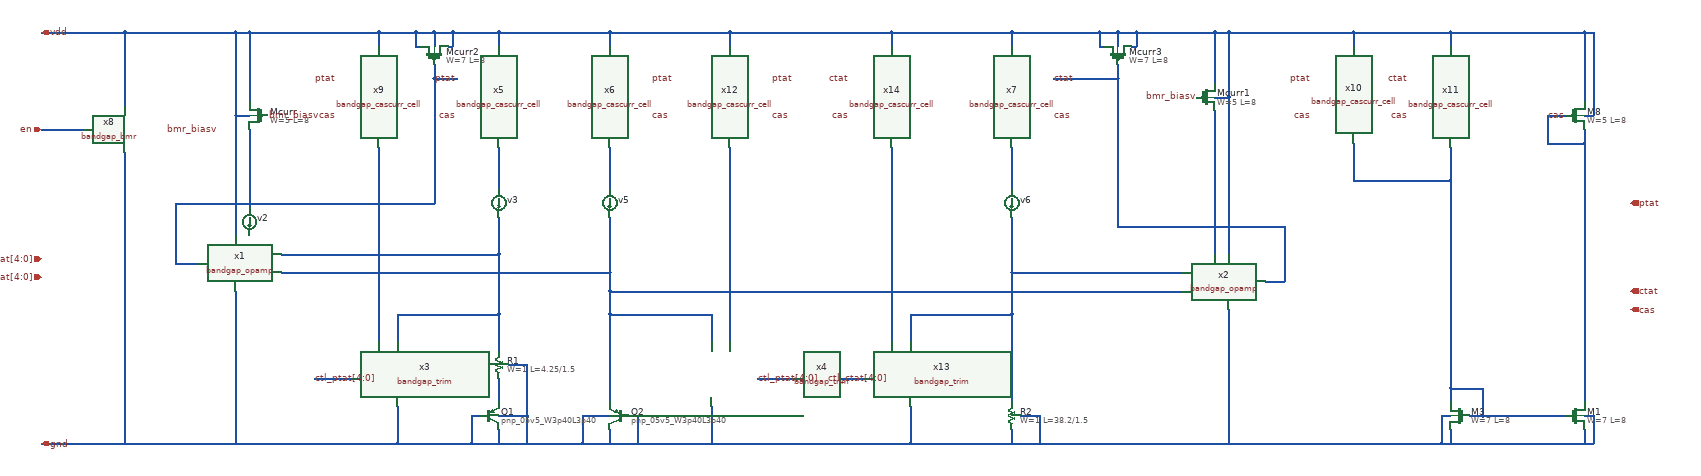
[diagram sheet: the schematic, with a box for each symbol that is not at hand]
v {xschem version=2.9.8 file_version=1.2}
G {}
K {}
V {}
S {}
E {}
N 1230 -280 1230 -90 {lab=#net1}
N 990 -410 990 -280 {lab=#net2}
N 990 -140 990 -90 {lab=#net3}
N 930 -60 950 -60 {lab=gnd}
N 930 -60 930 0 {lab=gnd}
N 930 0 990 0 {lab=gnd}
N 990 -30 990 0 {lab=gnd}
N 1230 -30 1230 0 {lab=gnd}
N 1230 0 1290 0 {lab=gnd}
N 1290 -60 1290 0 {lab=gnd}
N 1270 -60 1290 -60 {lab=gnd}
N 890 -890 990 -890 {lab=vdd}
N 990 -890 990 -860 {lab=vdd}
N 990 -890 1230 -890 {lab=vdd}
N 1230 -890 1230 -860 {lab=vdd}
N 1170 0 1230 0 {lab=gnd}
N 770 0 930 0 {lab=gnd}
N 2160 0 2570 0 {lab=gnd}
N 2100 -30 2100 0 {lab=gnd}
N 1230 -370 1230 -330 {lab=#net1}
N 1880 0 2100 0 {lab=gnd}
N 520 -410 990 -410 {lab=#net2}
N 520 -370 1230 -370 {lab=#net1}
N 290 -390 340 -390 {lab=ptat}
N 420 -330 420 0 {lab=gnd}
N 2570 -290 2570 0 {lab=gnd}
N 2100 -280 2100 -90 {lab=#net4}
N 2100 -370 2470 -370 {lab=#net4}
N 1840 -890 2100 -890 {lab=vdd}
N 420 -710 420 -450 {lab=vdd}
N 2570 -750 2570 -410 {lab=vdd}
N 2540 -890 2570 -890 {lab=vdd}
N 2100 -890 2100 -860 {lab=vdd}
N 3050 -890 3050 -860 {lab=vdd}
N 2840 -890 3050 -890 {lab=vdd}
N 2840 -890 2840 -860 {lab=vdd}
N 3050 -120 3050 -90 {lab=#net5}
N 2840 -650 2840 -570 {lab=#net5}
N 2840 -570 3050 -570 {lab=#net5}
N 3120 -60 3300 -60 {lab=#net5}
N 3050 -120 3120 -120 {lab=#net5}
N 3120 -120 3120 -60 {lab=#net5}
N 3050 0 3340 0 {lab=gnd}
N 3340 -30 3340 0 {lab=gnd}
N 3050 -30 3050 0 {lab=gnd}
N 3030 -60 3050 -60 {lab=gnd}
N 3030 -60 3030 0 {lab=gnd}
N 3340 -60 3360 -60 {lab=gnd}
N 3360 -60 3360 0 {lab=gnd}
N 3340 0 3360 0 {lab=gnd}
N 3340 -890 3340 -740 {lab=vdd}
N 3260 -710 3300 -710 {lab=cas}
N 3260 -710 3260 -650 {lab=cas}
N 3260 -650 3340 -650 {lab=cas}
N 3340 -680 3340 -650 {lab=cas}
N 3050 -890 3340 -890 {lab=vdd}
N 3340 -650 3340 -90 {lab=cas}
N 3340 -710 3360 -710 {lab=vdd}
N 3360 -890 3360 -710 {lab=vdd}
N 3340 -890 3360 -890 {lab=vdd}
N 2570 -890 2840 -890 {lab=vdd}
N 3050 -640 3050 -570 {lab=#net5}
N 3050 -570 3050 -120 {lab=#net5}
N 3090 -60 3120 -60 {lab=#net5}
N 3030 0 3050 0 {lab=gnd}
N 2570 0 3030 0 {lab=gnd}
N 2190 -790 2330 -790 {lab=ctat}
N 2690 -470 2690 -350 {lab=ctat}
N 2650 -350 2690 -350 {lab=ctat}
N 290 -520 290 -390 {lab=ptat}
N 290 -520 850 -520 {lab=ptat}
N 850 -790 850 -520 {lab=ptat}
N 850 -790 900 -790 {lab=ptat}
N 1230 -330 2470 -330 {lab=#net1}
N 180 -890 420 -890 {lab=vdd}
N 180 0 420 0 {lab=gnd}
N 990 -60 1050 -60 { lab=gnd}
N 1050 -60 1050 0 { lab=gnd}
N 1170 -60 1230 -60 { lab=gnd}
N 1170 -60 1170 0 { lab=gnd}
N 1010 -170 1050 -170 { lab=gnd}
N 1050 -170 1050 -60 { lab=gnd}
N 2120 -60 2160 -60 { lab=gnd}
N 2160 -60 2160 0 { lab=gnd}
N 990 0 1050 0 {lab=gnd}
N 1050 0 1170 0 {lab=gnd}
N 2100 0 2160 0 {lab=gnd}
N 990 -640 990 -550 { lab=#net6}
N 990 -490 990 -410 { lab=#net2}
N 1230 -490 1230 -370 { lab=#net1}
N 1230 -640 1230 -550 { lab=#net7}
N 2100 -490 2100 -370 { lab=#net4}
N 2100 -640 2100 -550 { lab=#net8}
N 450 -680 450 -510 { lab=#net9}
N 2330 -470 2690 -470 { lab=ctat}
N 2330 -790 2330 -470 {lab=ctat}
N 0 -890 180 -890 { lab=vdd}
N 180 -890 180 -730 { lab=vdd}
N 180 -630 180 0 { lab=gnd}
N 0 0 180 0 { lab=gnd}
N -0 -680 90 -680 { lab=en}
N 420 -710 450 -710 { lab=vdd}
N 450 -890 450 -740 { lab=vdd}
N 2540 -750 2570 -750 { lab=vdd}
N 2540 -890 2540 -780 { lab=vdd}
N 2370 -890 2540 -890 { lab=vdd}
N 420 -890 420 -710 {lab=vdd}
N 2570 -890 2570 -750 {lab=vdd}
N 420 -890 450 -890 {lab=vdd}
N 880 -860 890 -860 { lab=vdd}
N 890 -890 890 -860 { lab=vdd}
N 850 -890 850 -860 { lab=vdd}
N 850 -820 850 -790 { lab=ptat}
N 810 -860 820 -860 { lab=vdd}
N 810 -890 810 -860 { lab=vdd}
N 2330 -890 2330 -860 { lab=vdd}
N 2360 -860 2370 -860 { lab=vdd}
N 2370 -890 2370 -860 { lab=vdd}
N 2290 -860 2300 -860 { lab=vdd}
N 2290 -890 2290 -860 { lab=vdd}
N 2330 -820 2330 -790 { lab=ctat}
N 850 -890 890 -890 {lab=vdd}
N 2290 -890 2330 -890 { lab=vdd}
N 2330 -890 2370 -890 { lab=vdd}
N 810 -890 850 -890 {lab=vdd}
N 730 -890 810 -890 {lab=vdd}
N 2100 -890 2290 -890 { lab=vdd}
N 990 -280 990 -200 { lab=#net2}
N 730 -890 730 -860 {lab=vdd}
N 730 -640 730 -220 { lab=#net10}
N 770 -280 770 -220 { lab=gnd}
N 1450 -280 1450 -220 { lab=gnd}
N 1490 -890 1490 -860 {lab=vdd}
N 1490 -640 1490 -220 { lab=#net11}
N 1450 -80 1450 0 { lab=gnd}
N 770 -80 770 0 { lab=gnd}
N 590 -140 670 -140 { lab=ctl_ptat[4:0]}
N 1550 -140 1630 -140 { lab=ctl_ptat[4:0]}
N 1840 -890 1840 -860 {lab=vdd}
N 1840 -640 1840 -220 { lab=#net12}
N 1880 -280 1880 -220 { lab=gnd}
N 1880 -80 1880 0 { lab=gnd}
N 1700 -140 1780 -140 { lab=ctl_ctat[4:0]}
N 1230 -330 1230 -280 {lab=#net1}
N 420 0 770 0 {lab=gnd}
N 1290 0 1450 0 {lab=gnd}
N 1450 0 1880 0 {lab=gnd}
N 2100 -370 2100 -280 {lab=#net4}
N 1230 -890 1490 -890 {lab=vdd}
N 1490 -890 1840 -890 {lab=vdd}
N 450 -890 730 -890 {lab=vdd}
N 1880 -280 1980 -280 { lab=gnd}
N 2540 -720 2540 -680 { lab=#net13}
N 2540 -520 2540 -410 { lab=#net13}
N 770 -280 870 -280 { lab=gnd}
N 1350 -280 1450 -280 { lab=gnd}
N 2540 -680 2540 -520 { lab=#net13}
N 870 -280 990 -280 {}
N 1230 -280 1350 -280 {}
N 1980 -280 2100 -280 {}
C {bandgap_opamp/bandgap_opamp.sym} 420 -390 0 1 {name=x1}
C {bandgap_opamp/bandgap_opamp.sym} 2570 -350 0 0 {name=x2}
C {lab_wire.sym} 900 -790 0 0 {name=l1 sig_type=std_logic lab=ptat}
C {lab_wire.sym} 1320 -790 0 1 {name=l2 sig_type=std_logic lab=ptat}
C {lab_wire.sym} 2190 -790 0 1 {name=l3 sig_type=std_logic lab=ctat}
C {lab_wire.sym} 900 -710 0 0 {name=l4 sig_type=std_logic lab=cas}
C {lab_wire.sym} 1320 -710 0 1 {name=l5 sig_type=std_logic lab=cas}
C {lab_wire.sym} 2190 -710 0 1 {name=l6 sig_type=std_logic lab=cas}
C {lab_wire.sym} 2750 -710 0 0 {name=l7 sig_type=std_logic lab=cas}
C {lab_wire.sym} 2960 -710 0 0 {name=l8 sig_type=std_logic lab=cas}
C {lab_wire.sym} 2750 -790 0 0 {name=l9 sig_type=std_logic lab=ptat}
C {lab_wire.sym} 2960 -790 0 0 {name=l10 sig_type=std_logic lab=ctat}
C {lab_wire.sym} 3260 -710 0 1 {name=l11 sig_type=std_logic lab=cas}
C {iopin.sym} 0 -890 0 1 {name=p1 lab=vdd}
C {iopin.sym} 0 0 0 1 {name=p2 lab=gnd}
C {opin.sym} 3440 -520 0 0 {name=p3 lab=ptat}
C {opin.sym} 3440 -330 0 0 {name=p4 lab=ctat}
C {opin.sym} 3440 -290 0 0 {name=p5 lab=cas}
C {sky130_fd_pr/pfet_01v8_lvt.sym} 3320 -710 0 0 {name=M8
L=8
W=5
ad="'W * 0.29'" pd="'2 * (W + 0.29)'"
as="'W * 0.29'" ps="'2 * (W + 0.29)'"
nrd="'0.29 / W'" nrs="'0.29 / W'"
sa=0 sb=0 sd=0
nf=1 mult=1
model=pfet_01v8_lvt
spiceprefix=X
}
C {sky130_fd_pr/nfet_01v8_lvt.sym} 3070 -60 0 1 {name=M3
L=8
W=7
ad="[expr @W *0.29]" pd="[expr 2*(@W + 0.29)]"
as="[expr @W *0.29]" ps="[expr 2*(@W + 0.29)]"
nrd="[expr 0.29/@W ]" nrs="[expr 0.29/@W ]"
sa=0 sb=0 sd=0
nf=1 mult=2
model=nfet_01v8_lvt
spiceprefix=X
}
C {sky130_fd_pr/nfet_01v8_lvt.sym} 3320 -60 0 0 {name=M1
L=8
W=7
ad="[expr @W *0.29]" pd="[expr 2*(@W + 0.29)]"
as="[expr @W *0.29]" ps="[expr 2*(@W + 0.29)]"
nrd="[expr 0.29/@W ]" nrs="[expr 0.29/@W ]"
sa=0 sb=0 sd=0
nf=1 mult=2
model=nfet_01v8_lvt
spiceprefix=X
}
C {spice_probe.sym} 990 -410 0 0 {name=p6 analysis=tran voltage=0.4638}
C {spice_probe.sym} 1230 -370 0 0 {name=p7 analysis=tran voltage=0.09533}
C {spice_probe.sym} 2100 -370 0 0 {name=p8 analysis=tran voltage=0.09569}
C {spice_probe.sym} 2190 -710 0 0 {name=p12 analysis=tran voltage=0.6147}
C {ammeter.sym} 450 -480 0 0 {name=v2 current=6.7318e-06}
C {bandgap_cascurr_cell/bandgap_cascurr_cell.sym} 990 -750 0 0 {name=x5 m=8}
C {bandgap_cascurr_cell/bandgap_cascurr_cell.sym} 1230 -750 0 1 {name=x6 m=8}
C {bandgap_cascurr_cell/bandgap_cascurr_cell.sym} 2100 -750 0 1 {name=x7 m=8}
C {bandgap_cascurr_cell/bandgap_cascurr_cell.sym} 2840 -750 0 0 {name=x10 m=4}
C {bandgap_cascurr_cell/bandgap_cascurr_cell.sym} 3050 -750 0 0 {name=x11 m=4}
C {sky130_fd_pr/pnp_05v5.sym} 970 -60 0 0 {name=Q1
m=8
model=pnp_05v5_W3p40L3p40
spiceprefix=X
}
C {sky130_fd_pr/pnp_05v5.sym} 1250 -60 0 1 {name=Q2
m=1
model=pnp_05v5_W3p40L3p40
spiceprefix=X
}
C {ammeter.sym} 990 -520 0 0 {name=v3 current=2.2865e-11}
C {ammeter.sym} 1230 -520 0 0 {name=v5 current=2.5928e-11}
C {ammeter.sym} 2100 -520 0 0 {name=v6 current=4.5094e-06}
C {sky130_fd_pr/res_xhigh_po.sym} 990 -170 0 1 {name=R1
W=1
L=4.25/1.5
model=res_xhigh_po
spiceprefix=X
m=1}
C {sky130_fd_pr/res_xhigh_po.sym} 2100 -60 0 1 {name=R2
W=1
L=38.2/1.5
model=res_xhigh_po
spiceprefix=X
m=1}
C {spice_probe.sym} 450 -550 0 1 {name=p11 analysis=tran voltage=0.7914}
C {spice_probe.sym} 2390 -470 0 0 {name=p9 analysis=tran voltage=0.6147}
C {bandgap_bmr/bandgap_bmr.sym} 180 -680 0 0 {name=x8}
C {sky130_fd_pr/pfet_01v8_lvt.sym} 470 -710 0 1 {name=Mcurr
L=8
W=5
ad="'W * 0.29'" pd="'2 * (W + 0.29)'"
as="'W * 0.29'" ps="'2 * (W + 0.29)'"
nrd="'0.29 / W'" nrs="'0.29 / W'"
sa=0 sb=0 sd=0
nf=1 mult=1
model=pfet_01v8_lvt
spiceprefix=X
}
C {lab_wire.sym} 270 -680 0 1 {name=l12 sig_type=std_logic lab=bmr_biasv}
C {lab_wire.sym} 490 -710 0 1 {name=l13 sig_type=std_logic lab=bmr_biasv}
C {sky130_fd_pr/pfet_01v8_lvt.sym} 2520 -750 0 0 {name=Mcurr1
L=8
W=5
ad="'W * 0.29'" pd="'2 * (W + 0.29)'"
as="'W * 0.29'" ps="'2 * (W + 0.29)'"
nrd="'0.29 / W'" nrs="'0.29 / W'"
sa=0 sb=0 sd=0
nf=1 mult=1
model=pfet_01v8_lvt
spiceprefix=X
}
C {lab_wire.sym} 2500 -750 0 0 {name=l14 sig_type=std_logic lab=bmr_biasv}
C {sky130_fd_pr/pfet_01v8_lvt.sym} 850 -840 1 1 {name=Mcurr2
L=8
W=7
ad="'W * 0.29'" pd="'2 * (W + 0.29)'"
as="'W * 0.29'" ps="'2 * (W + 0.29)'"
nrd="'0.29 / W'" nrs="'0.29 / W'"
sa=0 sb=0 sd=0
nf=1 mult=16
model=pfet_01v8_lvt
spiceprefix=X
}
C {sky130_fd_pr/pfet_01v8_lvt.sym} 2330 -840 1 1 {name=Mcurr3
L=8
W=7
ad="'W * 0.29'" pd="'2 * (W + 0.29)'"
as="'W * 0.29'" ps="'2 * (W + 0.29)'"
nrd="'0.29 / W'" nrs="'0.29 / W'"
sa=0 sb=0 sd=0
nf=1 mult=48
model=pfet_01v8_lvt
spiceprefix=X
}
C {bandgap_trim/bandgap_trim.sym} 690 -100 0 0 {name=x3}
C {bandgap_trim/bandgap_trim.sym} 1530 -100 0 1 {name=x4}
C {lab_wire.sym} 640 -790 0 0 {name=l15 sig_type=std_logic lab=ptat}
C {lab_wire.sym} 640 -710 0 0 {name=l16 sig_type=std_logic lab=cas}
C {bandgap_cascurr_cell/bandgap_cascurr_cell.sym} 730 -750 0 0 {name=x9 m=4}
C {lab_wire.sym} 1580 -790 0 1 {name=l17 sig_type=std_logic lab=ptat}
C {lab_wire.sym} 1580 -710 0 1 {name=l18 sig_type=std_logic lab=cas}
C {bandgap_cascurr_cell/bandgap_cascurr_cell.sym} 1490 -750 0 1 {name=x12 m=4}
C {lab_wire.sym} 590 -140 0 1 {name=l19 sig_type=std_logic lab=ctl_ptat[4:0]}
C {lab_wire.sym} 1550 -140 0 1 {name=l20 sig_type=std_logic lab=ctl_ptat[4:0]}
C {bandgap_trim/bandgap_trim.sym} 1800 -100 0 0 {name=x13}
C {lab_wire.sym} 1750 -790 0 0 {name=l21 sig_type=std_logic lab=ctat}
C {lab_wire.sym} 1750 -710 0 0 {name=l22 sig_type=std_logic lab=cas}
C {bandgap_cascurr_cell/bandgap_cascurr_cell.sym} 1840 -750 0 0 {name=x14 m=4}
C {lab_wire.sym} 1700 -140 0 1 {name=l23 sig_type=std_logic lab=ctl_ctat[4:0]}
C {ipin.sym} 0 -680 0 0 {name=p10 lab=en}
C {ipin.sym} 0 -400 0 0 {name=p13 lab=ctl_ptat[4:0]}
C {ipin.sym} 0 -360 0 0 {name=p14 lab=ctl_ctat[4:0]}
